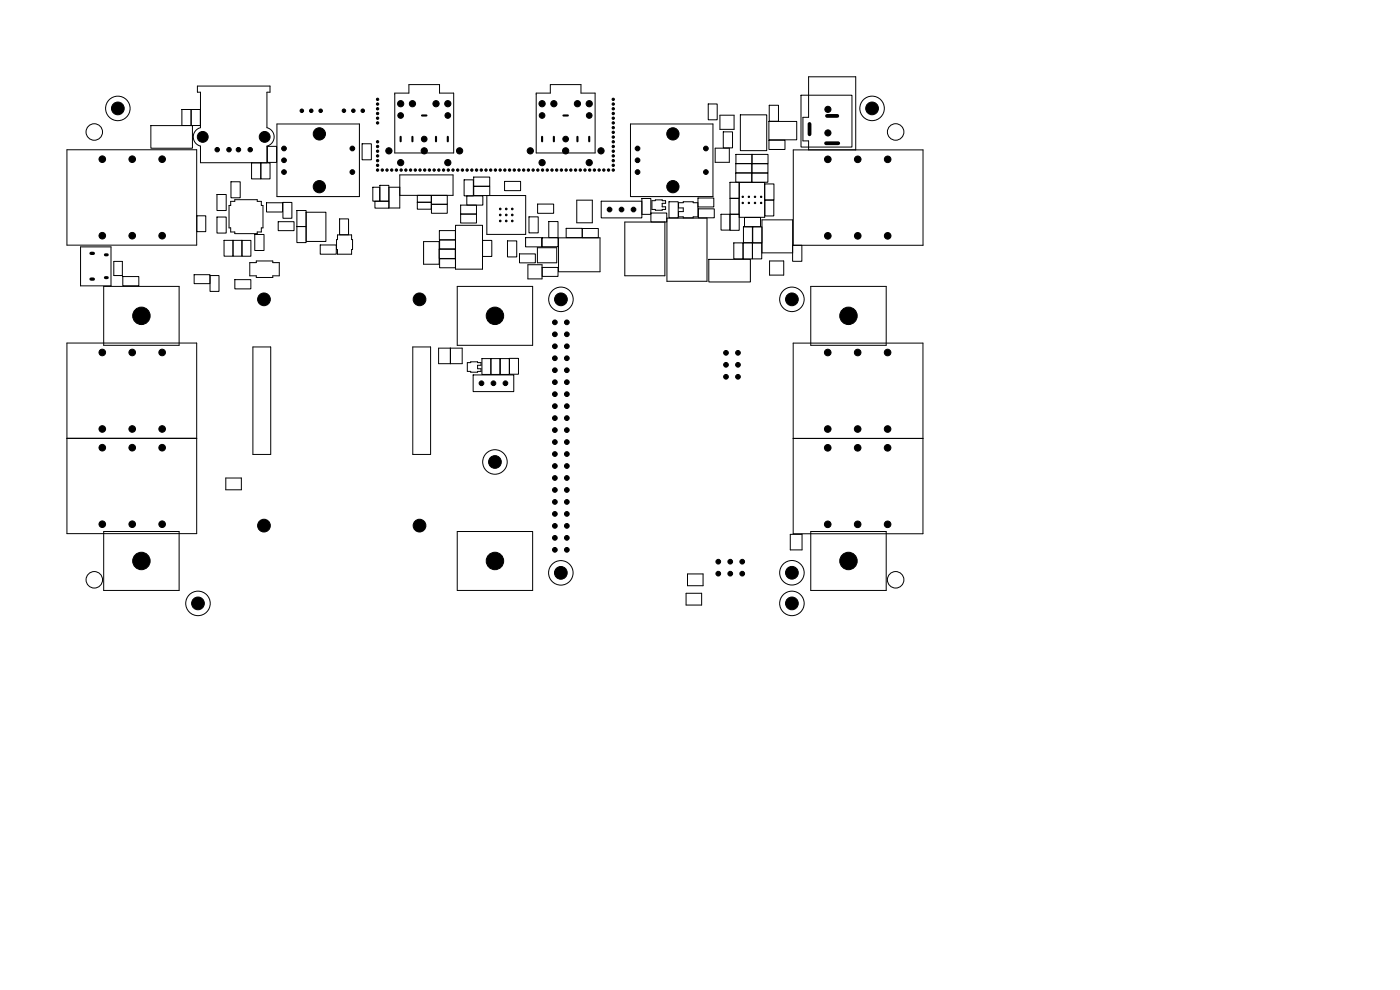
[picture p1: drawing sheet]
<svg xmlns="http://www.w3.org/2000/svg" width="297mm" height="210mm" viewBox="0 0 297 210" stroke-linecap="round" stroke-linejoin="round" font-family="sans-serif">
<g fill="none" stroke="#000" stroke-width=".21">
<path d="M41.9 18.3h15.4v1.3h-.7v7.5a2.01 2.01 0 0 1 1.6 1.9 2.01 2.01 0 0 1-1.6 2v3.5h-14.1v-3.5a2.01 2.01 0 0 1-1.5-2 2.01 2.01 0 0 1 1.5-1.9v-7.5h-.6zM83.7 19.8h3v-1.8h6.5v1.8h3v12.7h-12.5zM113.7 19.8h3v-1.8h6.5v1.8h3v12.7h-12.5zM171.5 16.3h10v15.5h-10v-1.9h-1.2v-5h1.2zM14.2 31.8h27.5v20.2h-27.5zM32 26.6h8.8v4.8h-8.8zM38.6 23.2h1.9v3.4h-1.9zM40.5 23.2h2v3.4h-2zM49 38.6h2v3.4h-2zM53.4 34.6h1.9v3.3h-1.9zM55.3 34.6h2v3.3h-2zM56.7 31h2v3.5h-2z"/>
<path d="M58.8 26.3h17.4v15.4h-17.4zM76.8 30.5h2v3.4h-2zM79.1 39.7h1.5v3h-1.5zM80.6 39.3h1.9v3.4h-1.9zM84.8 39.7h-2.3v4.4h2.3v-7h11.3v4.3h-11.3M98.5 38.2h1.9v3.4h-1.9zM100.5 37.6h3.4v1.9h-3.4zM100.5 39.5h3.4v2h-3.4zM107 38.5h3.4v1.9h-3.4zM133.7 26.3h17.5v15.4h-17.5zM150.2 22.1h1.9v3.3h-1.9zM151.7 31.4h3v3h-3z"/>
<path d="M152.7 24.4h3v3h-3zM153.4 28h2v3.4h-2zM154.9 38.7h1.9v3.4h-1.9zM156.1 36.7h3.4v1.9h-3.4zM156.1 34.7h3.4v2h-3.4zM156.1 32.8h3.4v1.9h-3.4zM156.8 38.7h5.4v7.4h-5.4zM157.1 24.4h5.6v7.6h-5.6zM159.5 36.7h3.4v2h-3.4zM159.5 34.7h3.4v2h-3.4zM159.5 32.8h3.4v1.9h-3.4zM162.2 39h2v3.4h-2z"/>
<path d="M163.1 25.8h5.9v3.9h-5.9zM163.1 29.8h3.4v1.9h-3.4zM163.2 22.3h2v3.4h-2zM168.3 31.8h27.5v20.2h-27.5zM169.9 20.2h10.8v11h-10.8zM17.1 52.4h6.4v8.2h-6.4zM24.1 55.5h1.9v3h-1.9zM26 58.7h3.5v1.9h-3.5zM41.2 58.3h3.3v1.9h-3.3zM41.7 45.8h1.9v3.3h-1.9zM44.6 58.5h1.9v3.3h-1.9zM46 41.3h2v3.4h-2z"/>
<path d="M46 46h2v3.4h-2zM47.5 51h1.9v3.3h-1.9zM48.9 42.7h.9v-.3h4.8v.3h.8v.9h.4v4.7h-.4v.9h-.8v.4h-4.8v-.4h-.9v-.9h-.3v-4.7h.3zM49.4 51h1.9v3.3h-1.9zM49.8 59.3h3.4v2h-3.4zM51.3 51h1.9v3.4h-1.9zM53 55.7h1.4v-.3h3.5v.3h1.3v2.8h-1.3v.4h-3.5v-.4h-1.4zM54 49.7h2v3.4h-2zM56.5 43h3.4v2h-3.4zM59 47h3.4v1.9h-3.4zM60 42.9h1.9v3.4h-1.9zM63 44.7h1.9v3.4h-1.9z"/>
<path d="M63 48.1h1.9v3.4h-1.9zM64.9 45h4.2v6.2h-4.2zM67.9 52h3.4v1.9h-3.4zM71.6 49.8h3v1h.2v2.1h-.2v1h-3v-1h-.2v-2.1h.2zM72 46.4h1.9v3.4h-1.9zM79.5 42.7h3v1.5h-3zM88.5 42.9h3v1.5h-3zM88.5 41.4h3v1.5h-3zM89.9 51.3h3.3v4.8h-3.3zM91.5 41.4h3.4v1.9h-3.4zM91.5 43.3h3.4v1.9h-3.4zM93.2 52.9h3.4v1.9h-3.4z"/>
<path d="M93.2 48.9h3.4v2h-3.4zM93.3 54.9h3.3v1.9h-3.3zM93.3 50.9h3.3v1.9h-3.3zM96.6 47.8h5.8v9.3h-5.8zM97.7 43.5h3.4v1.9h-3.4zM97.7 45.4h3.4v1.9h-3.4zM99 41.6h3.4v1.9h-3.4zM102.4 51h1.9v3.4h-1.9zM103.3 41.5h8.2v8.2h-8.2zM107.7 51.1h1.9v3.4h-1.9zM110.2 53.9h3.4v1.9h-3.4zM111.5 50.4h3.4v2h-3.4z"/>
<path d="M112 56.2h3v3h-3zM112.2 46h2v3.4h-2zM114 52.5h4.1v3.2h-4.1zM114.1 43.3h3.4v2h-3.4zM115 56.7h3.4v1.9h-3.4zM115 50.4h3.4v1.9h-3.4zM116.4 47h2v3.4h-2zM118.5 50.5h8.8v7.2h-8.8zM120.1 48.4h3.4v2h-3.4zM122.4 42.5h3.3v4.8h-3.3zM123.5 48.5h3.4v1.9h-3.4zM127.5 42.7h8.7v3.5h-8.7z"/>
<path d="M132.5 47.1h8.5v11.4h-8.5zM136.2 42.1h1.9v3.4h-1.9zM138.1 45.2h3.3v1.9h-3.3zM138.3 42.6h.7v-.2h1.5v.2h.7v.5h-.7v.8h.7v.5h-.7v.2h-1.5v-.2h-.7zM141.5 46.3h8.5v13.4h-8.5zM141.9 42.8h2v3.4h-2zM143.9 43h1v-.2h2.1v.2h1v3h-1v.2h-2.1v-.2h-1v-1.1h1v-.8h-1zM148.1 42h3.3v1.9h-3.3zM148.2 44.3h3.3v1.9h-3.3zM150.4 55h8.8v4.8h-8.8zM153 45.5h1.9v3.3h-1.9zM154.9 45.5h1.9v3.4h-1.9z"/>
<path d="M154.9 42.1h1.9v3.4h-1.9zM155.7 51.5h1.9v3.4h-1.9zM157.6 51.5h2v3.4h-2zM157.7 48.1h1.9v3.4h-1.9zM157.9 46.1h3.4v2h-3.4zM159.6 51.5h2v3.4h-2zM159.7 48.1h1.9v3.4h-1.9zM161.6 46.6h6.6v7h-6.6zM162.3 42.5h1.9v3.3h-1.9zM163.3 55.4h3v3h-3zM168.2 52h1.9v3.4h-1.9zM14.2 72.8h27.5v40.4h-27.5z"/>
<path d="M22 60.8h16v12.5h-16zM53.6 73.6h3.8v22.8h-3.8zM87.6 73.6h3.7v22.8h-3.7zM93.1 73.9h5v3.3h-5zM95.5 73.9v3.3M97 60.8h16v12.5h-16zM99.1 76.9h.8v-.1h1.4v.1h.7v.6h-.7v.7h.7v.6h-.7v.2h-1.4v-.2h-.8zM100.4 79.5h8.6v3.6h-8.6zM102.2 76.1h1.9v3.3h-1.9zM104.1 76.1h1.9v3.3h-1.9zM106.1 76.1h1.9v3.3h-1.9zM108.1 76h1.9v3.4h-1.9z"/>
<path d="M168.3 72.8h27.5v40.4h-27.5zM172 60.8h16v12.5h-16zM14.2 93h27.5M168.3 93h27.5M22 112.8h16v12.5h-16zM47.9 101.4h3.3v2.5h-3.3zM97 112.8h16v12.5h-16zM167.6 113.4h2.5v3.3h-2.5zM172 112.8h16v12.5h-16zM145.5 125.9h3.4v2.5h-3.4zM145.9 121.8h3.2v2.5h-3.2z"/>
<circle cx="20" cy="28" r="1.75"/>
<circle cx="25" cy="23" r="2.6"/>
<circle cx="185" cy="23" r="2.6"/>
<circle cx="190" cy="28" r="1.75"/>
<circle cx="119" cy="63.5" r="2.6"/>
<circle cx="168" cy="63.5" r="2.6"/>
<circle cx="105" cy="98" r="2.6"/>
<circle cx="20" cy="123" r="1.75"/>
<circle cx="42" cy="128" r="2.6"/>
<circle cx="119" cy="121.5" r="2.6"/>
<circle cx="168" cy="128" r="2.6"/>
<circle cx="168" cy="121.5" r="2.6"/>
<circle cx="190" cy="123" r="1.75"/>
</g>
<g fill="#000" stroke="#000" stroke-width=".21">
<circle cx="21.7" cy="33.8" r=".7"/>
<circle cx="25" cy="23" r="1.35"/>
<circle cx="28" cy="33.8" r=".7"/>
<circle cx="34.4" cy="33.8" r=".7"/>
<circle cx="43" cy="29" r="1.15"/>
<circle cx="46.1" cy="31.8" r=".47"/>
<circle cx="48.6" cy="31.8" r=".47"/>
<circle cx="50.6" cy="31.8" r=".47"/>
<circle cx="53.1" cy="31.8" r=".47"/>
<circle cx="56.1" cy="29" r="1.15"/>
<circle cx="60.2" cy="36.5" r=".5"/>
<circle cx="60.2" cy="31.5" r=".5"/>
<circle cx="60.2" cy="34" r=".5"/>
<circle cx="64" cy="23.5" r=".38"/>
<circle cx="66" cy="23.5" r=".38"/>
<circle cx="67.7" cy="28.4" r="1.3"/>
<circle cx="67.7" cy="39.6" r="1.3"/>
<circle cx="68" cy="23.5" r=".38"/>
<circle cx="73" cy="23.5" r=".37"/>
<circle cx="74.8" cy="36.5" r=".5"/>
<circle cx="74.8" cy="31.5" r=".5"/>
<circle cx="75" cy="23.5" r=".37"/>
<circle cx="77" cy="23.5" r=".37"/>
<circle cx="80.1" cy="22.1" r=".25"/>
<circle cx="80.1" cy="25.1" r=".25"/>
<circle cx="80.1" cy="23.1" r=".25"/>
<circle cx="80.1" cy="24.1" r=".25"/>
<circle cx="80.1" cy="21.1" r=".25"/>
<circle cx="80.1" cy="26.1" r=".25"/>
<circle cx="80.1" cy="32.1" r=".25"/>
<circle cx="80.1" cy="33.1" r=".25"/>
<circle cx="80.1" cy="35.1" r=".25"/>
<circle cx="80.1" cy="30.1" r=".25"/>
<circle cx="80.1" cy="34.1" r=".25"/>
<circle cx="80.1" cy="31.1" r=".25"/>
<circle cx="80.1" cy="36.1" r=".25"/>
<circle cx="81.1" cy="36.1" r=".25"/>
<circle cx="82.1" cy="36.1" r=".25"/>
<circle cx="82.5" cy="32" r=".66"/>
<circle cx="83.1" cy="36.1" r=".25"/>
<circle cx="84.1" cy="36.1" r=".25"/>
<circle cx="85" cy="24.5" r=".6"/>
<circle cx="85" cy="34.5" r=".66"/>
<circle cx="85" cy="22" r=".66"/>
<circle cx="85.1" cy="36.1" r=".25"/>
<circle cx="86.1" cy="36.1" r=".25"/>
<circle cx="87.1" cy="36.1" r=".25"/>
<circle cx="87.5" cy="22" r=".66"/>
<circle cx="88.1" cy="36.1" r=".25"/>
<circle cx="89.1" cy="36.1" r=".25"/>
<circle cx="90" cy="29.5" r=".6"/>
<circle cx="90" cy="32" r=".66"/>
<circle cx="90.1" cy="36.1" r=".25"/>
<circle cx="91.1" cy="36.1" r=".25"/>
<circle cx="92.1" cy="36.1" r=".25"/>
<circle cx="92.5" cy="22" r=".66"/>
<circle cx="93.1" cy="36.1" r=".25"/>
<circle cx="94.1" cy="36.1" r=".25"/>
<circle cx="95" cy="24.5" r=".6"/>
<circle cx="95" cy="34.5" r=".66"/>
<circle cx="95" cy="22" r=".66"/>
<circle cx="95.1" cy="36.1" r=".25"/>
<circle cx="96.1" cy="36.1" r=".25"/>
<circle cx="97.1" cy="36.1" r=".25"/>
<circle cx="97.5" cy="32" r=".66"/>
<circle cx="98.1" cy="36.1" r=".25"/>
<circle cx="99.1" cy="36.1" r=".25"/>
<circle cx="100.1" cy="36.1" r=".25"/>
<circle cx="101.1" cy="36.1" r=".25"/>
<circle cx="102.1" cy="36.1" r=".25"/>
<circle cx="103.1" cy="36.1" r=".25"/>
<circle cx="104.1" cy="36.1" r=".25"/>
<circle cx="105.1" cy="36.1" r=".25"/>
<circle cx="106.1" cy="36.1" r=".25"/>
<circle cx="107.1" cy="36.1" r=".25"/>
<circle cx="108.1" cy="36.1" r=".25"/>
<circle cx="109.1" cy="36.1" r=".25"/>
<circle cx="110.1" cy="36.1" r=".25"/>
<circle cx="111.1" cy="36.1" r=".25"/>
<circle cx="112.1" cy="36.1" r=".25"/>
<circle cx="112.5" cy="32" r=".66"/>
<circle cx="113.1" cy="36.1" r=".25"/>
<circle cx="114.1" cy="36.1" r=".25"/>
<circle cx="115" cy="34.5" r=".66"/>
<circle cx="115" cy="22" r=".66"/>
<circle cx="115" cy="24.5" r=".6"/>
<circle cx="115.1" cy="36.1" r=".25"/>
<circle cx="116.1" cy="36.1" r=".25"/>
<circle cx="117.1" cy="36.1" r=".25"/>
<circle cx="117.5" cy="22" r=".66"/>
<circle cx="118.1" cy="36.1" r=".25"/>
<circle cx="119.1" cy="36.1" r=".25"/>
<circle cx="120" cy="29.5" r=".6"/>
<circle cx="120" cy="32" r=".66"/>
<circle cx="120.1" cy="36.1" r=".25"/>
<circle cx="121.1" cy="36.1" r=".25"/>
<circle cx="122.1" cy="36.1" r=".25"/>
<circle cx="122.5" cy="22" r=".66"/>
<circle cx="123.1" cy="36.1" r=".25"/>
<circle cx="124.1" cy="36.1" r=".25"/>
<circle cx="125" cy="34.5" r=".66"/>
<circle cx="125" cy="22" r=".66"/>
<circle cx="125" cy="24.5" r=".6"/>
<circle cx="125.1" cy="36.1" r=".25"/>
<circle cx="126.1" cy="36.1" r=".25"/>
<circle cx="127.1" cy="36.1" r=".25"/>
<circle cx="127.5" cy="32" r=".66"/>
<circle cx="128.1" cy="36.1" r=".25"/>
<circle cx="129.1" cy="36.1" r=".25"/>
<circle cx="130.1" cy="28.1" r=".25"/>
<circle cx="130.1" cy="27.1" r=".25"/>
<circle cx="130.1" cy="22.1" r=".25"/>
<circle cx="130.1" cy="25.1" r=".25"/>
<circle cx="130.1" cy="23.1" r=".25"/>
<circle cx="130.1" cy="24.1" r=".25"/>
<circle cx="130.1" cy="26.1" r=".25"/>
<circle cx="130.1" cy="21.1" r=".25"/>
<circle cx="130.1" cy="32.1" r=".25"/>
<circle cx="130.1" cy="35.1" r=".25"/>
<circle cx="130.1" cy="33.1" r=".25"/>
<circle cx="130.1" cy="30.1" r=".25"/>
<circle cx="130.1" cy="34.1" r=".25"/>
<circle cx="130.1" cy="29.1" r=".25"/>
<circle cx="130.1" cy="36.1" r=".25"/>
<circle cx="130.1" cy="31.1" r=".25"/>
<circle cx="135.3" cy="36.5" r=".5"/>
<circle cx="135.3" cy="31.5" r=".5"/>
<circle cx="135.3" cy="34" r=".5"/>
<circle cx="142.8" cy="28.4" r="1.3"/>
<circle cx="142.8" cy="39.6" r="1.3"/>
<circle cx="149.7" cy="31.5" r=".5"/>
<circle cx="149.7" cy="36.5" r=".5"/>
<circle cx="175.6" cy="33.8" r=".7"/>
<circle cx="175.6" cy="23.2" r=".65"/>
<circle cx="175.6" cy="28.2" r=".65"/>
<circle cx="182" cy="33.8" r=".7"/>
<circle cx="185" cy="23" r="1.35"/>
<circle cx="188.3" cy="33.8" r=".7"/>
<circle cx="21.7" cy="50" r=".7"/>
<circle cx="28" cy="50" r=".7"/>
<circle cx="34.4" cy="50" r=".7"/>
<circle cx="106.1" cy="46.9" r=".17"/>
<circle cx="106.1" cy="44.3" r=".17"/>
<circle cx="106.1" cy="45.6" r=".17"/>
<circle cx="107.4" cy="46.9" r=".17"/>
<circle cx="107.4" cy="45.6" r=".17"/>
<circle cx="107.4" cy="44.3" r=".17"/>
<circle cx="108.7" cy="46.9" r=".17"/>
<circle cx="108.7" cy="44.3" r=".17"/>
<circle cx="108.7" cy="45.6" r=".17"/>
<circle cx="129.3" cy="44.5" r=".5"/>
<circle cx="131.9" cy="44.5" r=".5"/>
<circle cx="134.4" cy="44.5" r=".5"/>
<circle cx="157.6" cy="41.8" r=".15"/>
<circle cx="157.6" cy="43.1" r=".15"/>
<circle cx="158.9" cy="43.1" r=".15"/>
<circle cx="158.9" cy="41.8" r=".15"/>
<circle cx="160.2" cy="43.1" r=".15"/>
<circle cx="160.2" cy="41.8" r=".15"/>
<circle cx="161.5" cy="43.1" r=".15"/>
<circle cx="161.5" cy="41.8" r=".15"/>
<circle cx="175.6" cy="50" r=".7"/>
<circle cx="182" cy="50" r=".7"/>
<circle cx="188.3" cy="50" r=".7"/>
<circle cx="21.7" cy="74.8" r=".7"/>
<circle cx="28" cy="74.8" r=".7"/>
<circle cx="30" cy="67" r="1.85"/>
<circle cx="34.4" cy="74.8" r=".7"/>
<circle cx="56" cy="63.5" r="1.35"/>
<circle cx="89" cy="63.5" r="1.35"/>
<circle cx="105" cy="67" r="1.85"/>
<circle cx="117.7" cy="70.9" r=".5"/>
<circle cx="117.7" cy="78.5" r=".5"/>
<circle cx="117.7" cy="76" r=".5"/>
<circle cx="117.7" cy="68.4" r=".5"/>
<circle cx="117.7" cy="73.5" r=".5"/>
<circle cx="119" cy="63.5" r="1.35"/>
<circle cx="120.3" cy="68.4" r=".5"/>
<circle cx="120.3" cy="78.5" r=".5"/>
<circle cx="120.3" cy="70.9" r=".5"/>
<circle cx="120.3" cy="73.5" r=".5"/>
<circle cx="120.3" cy="76" r=".5"/>
<circle cx="154" cy="74.8" r=".5"/>
<circle cx="154" cy="77.4" r=".5"/>
<circle cx="154" cy="79.9" r=".5"/>
<circle cx="156.6" cy="74.8" r=".5"/>
<circle cx="156.6" cy="77.4" r=".5"/>
<circle cx="156.6" cy="79.9" r=".5"/>
<circle cx="168" cy="63.5" r="1.35"/>
<circle cx="175.6" cy="74.8" r=".7"/>
<circle cx="180" cy="67" r="1.85"/>
<circle cx="181.9" cy="74.8" r=".7"/>
<circle cx="188.3" cy="74.8" r=".7"/>
<circle cx="21.7" cy="95" r=".7"/>
<circle cx="21.7" cy="91" r=".7"/>
<circle cx="28" cy="95" r=".7"/>
<circle cx="28" cy="91" r=".7"/>
<circle cx="34.4" cy="95" r=".7"/>
<circle cx="34.4" cy="91" r=".7"/>
<circle cx="102.1" cy="81.3" r=".5"/>
<circle cx="104.7" cy="81.3" r=".5"/>
<circle cx="105" cy="98" r="1.35"/>
<circle cx="107.2" cy="81.3" r=".5"/>
<circle cx="117.7" cy="83.6" r=".5"/>
<circle cx="117.7" cy="93.8" r=".5"/>
<circle cx="117.7" cy="86.2" r=".5"/>
<circle cx="117.7" cy="91.2" r=".5"/>
<circle cx="117.7" cy="98.9" r=".5"/>
<circle cx="117.7" cy="81.1" r=".5"/>
<circle cx="117.7" cy="96.3" r=".5"/>
<circle cx="117.7" cy="88.7" r=".5"/>
<circle cx="120.3" cy="96.3" r=".5"/>
<circle cx="120.3" cy="93.8" r=".5"/>
<circle cx="120.3" cy="81.1" r=".5"/>
<circle cx="120.3" cy="83.6" r=".5"/>
<circle cx="120.3" cy="86.2" r=".5"/>
<circle cx="120.3" cy="88.7" r=".5"/>
<circle cx="120.3" cy="98.9" r=".5"/>
<circle cx="120.3" cy="91.2" r=".5"/>
<circle cx="175.6" cy="91" r=".7"/>
<circle cx="175.6" cy="95" r=".7"/>
<circle cx="181.9" cy="91" r=".7"/>
<circle cx="181.9" cy="95" r=".7"/>
<circle cx="188.3" cy="91" r=".7"/>
<circle cx="188.3" cy="95" r=".7"/>
<circle cx="21.7" cy="111.2" r=".7"/>
<circle cx="28" cy="111.2" r=".7"/>
<circle cx="30" cy="119" r="1.85"/>
<circle cx="34.4" cy="111.2" r=".7"/>
<circle cx="56" cy="111.5" r="1.35"/>
<circle cx="89" cy="111.5" r="1.35"/>
<circle cx="105" cy="119" r="1.85"/>
<circle cx="117.7" cy="114.1" r=".5"/>
<circle cx="117.7" cy="103.9" r=".5"/>
<circle cx="117.7" cy="101.4" r=".5"/>
<circle cx="117.7" cy="116.6" r=".5"/>
<circle cx="117.7" cy="106.5" r=".5"/>
<circle cx="117.7" cy="109" r=".5"/>
<circle cx="117.7" cy="111.6" r=".5"/>
<circle cx="120.3" cy="103.9" r=".5"/>
<circle cx="120.3" cy="111.6" r=".5"/>
<circle cx="120.3" cy="101.4" r=".5"/>
<circle cx="120.3" cy="109" r=".5"/>
<circle cx="120.3" cy="116.6" r=".5"/>
<circle cx="120.3" cy="106.5" r=".5"/>
<circle cx="120.3" cy="114.1" r=".5"/>
<circle cx="152.4" cy="119.2" r=".5"/>
<circle cx="154.9" cy="119.2" r=".5"/>
<circle cx="157.5" cy="119.2" r=".5"/>
<circle cx="175.6" cy="111.2" r=".7"/>
<circle cx="180" cy="119" r="1.85"/>
<circle cx="181.9" cy="111.2" r=".7"/>
<circle cx="188.3" cy="111.2" r=".7"/>
<circle cx="42" cy="128" r="1.35"/>
<circle cx="119" cy="121.5" r="1.35"/>
<circle cx="152.4" cy="121.7" r=".5"/>
<circle cx="154.9" cy="121.7" r=".5"/>
<circle cx="157.5" cy="121.7" r=".5"/>
<circle cx="168" cy="121.5" r="1.35"/>
<circle cx="168" cy="128" r="1.35"/>
</g>
<path d="M85 29v1M87.5 29v1M89.5 24.5h1M92.5 29v1M95 29v1M115 29v1M117.5 29v1M119.5 24.5h1M122.5 29v1M125 29v1" fill="none" stroke="#000" stroke-width=".45"/>
<path d="M171.7 26.3v2.2M175.2 30.4h2.6M175.4 24.6h2.2" fill="none" stroke="#000" stroke-width=".8"/>
<path d="M19.3 53.7h.5M19.3 59.2h.5" fill="none" stroke="#000" stroke-width=".7"/>
<path d="M22.4 54.1h.4M22.4 58.9h.4" fill="none" stroke="#000" stroke-width=".65"/>
</svg>
